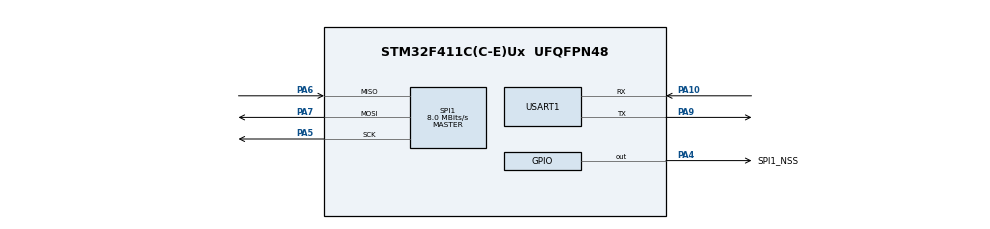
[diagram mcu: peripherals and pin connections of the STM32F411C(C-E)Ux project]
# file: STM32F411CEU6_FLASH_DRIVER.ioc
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Mcu.Family=STM32F4
Mcu.Name=STM32F411C(C-E)Ux
Mcu.Package=UFQFPN48
NVIC.PriorityGroup=NVIC_PRIORITYGROUP_4
PA10.Mode=Asynchronous
PA10.Signal=USART1_RX
PA4.GPIO_Label=SPI1_NSS
PA4.PinState=GPIO_PIN_SET
PA4.Signal=GPIO_Output
PA5.Mode=Full_Duplex_Master
PA5.Signal=SPI1_SCK
PA6.Mode=Full_Duplex_Master
PA6.Signal=SPI1_MISO
PA7.Mode=Full_Duplex_Master
PA7.Signal=SPI1_MOSI
PA9.Mode=Asynchronous
PA9.Signal=USART1_TX
ProjectManager.HeapSize=0x200
ProjectManager.StackSize=0x400
ProjectManager.TargetToolchain=CMake
RCC.AHBFreq_Value=16000000
RCC.APB1Freq_Value=16000000
RCC.APB2Freq_Value=16000000
RCC.CortexFreq_Value=16000000
RCC.HSE_VALUE=25000000
RCC.HSI_VALUE=16000000
RCC.LSE_VALUE=32768
RCC.SYSCLKFreq_VALUE=16000000
RCC.VCOOutputFreq_Value=192000000
SPI1.CalculateBaudRate=8.0 MBits/s
SPI1.Direction=SPI_DIRECTION_2LINES
SPI1.Mode=SPI_MODE_MASTER
SPI1.VirtualType=VM_MASTER
USART1.VirtualMode=VM_ASYNC
board=custom

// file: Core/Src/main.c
/* USER CODE BEGIN Header */
/**
  ******************************************************************************
  * @file           : main.c
  * @brief          : Main program body
  ******************************************************************************
  * @attention
  *
  * Copyright (c) 2026 STMicroelectronics.
  * All rights reserved.
  *
  * This software is licensed under terms that can be found in the LICENSE file
  * in the root directory of this software component.
  * If no LICENSE file comes with this software, it is provided AS-IS.
  *
  ******************************************************************************
  */
/* USER CODE END Header */
#include "main.h"

/* USER CODE BEGIN Includes */
#include "gpio.h"
#include "spi.h"
#include "usart.h"
#include "w25q128.h"
#include "uart_bootloader.h"
#include <stdio.h>
#include <string.h>
/* USER CODE END Includes */

/* USER CODE BEGIN PV */
W25Q128_Handle_t hflash;
BOOT_Handle_t hboot;
/* USER CODE END PV */

void SystemClock_Config(void);

/* USER CODE BEGIN 0 */

// Redirect printf to SWO/ITM for debug console
int _write(int file, char *ptr, int len)
{
  for (int i = 0; i < len; i++)
  {
    ITM_SendChar((*ptr++));
  }
  return len;
}

/* USER CODE END 0 */

int main(void)
{

  /* MCU Configuration--------------------------------------------------------*/

  /* Reset of all peripherals, Initializes the Flash interface and the Systick. */
  HAL_Init();

  /* Configure the system clock */
  SystemClock_Config();

  /* Initialize all configured peripherals */
  MX_GPIO_Init();
  MX_SPI1_Init();
  MX_USART1_UART_Init();
  /* USER CODE BEGIN 2 */

  // Initialize W25Q128 Flash
  W25Q128_Init(&hflash, &hspi1, SPI1_NSS_GPIO_Port, SPI1_NSS_Pin);

  // Read and verify flash ID
  uint8_t mfg_id, dev_id;
  if (W25Q128_ReadID(&hflash, &mfg_id, &dev_id) == W25Q128_OK)
  {
    // Print to both UART and Debug Console (SWO)
    printf("W25Q128 Found! MFG: 0x%02X, DEV: 0x%02X\r\n", mfg_id, dev_id);

    char msg[50];
    sprintf(msg, "W25Q128 Found! MFG: 0x%02X, DEV: 0x%02X\r\n", mfg_id, dev_id);
    HAL_UART_Transmit(&huart1, (uint8_t*)msg, strlen(msg), 1000);
  }
  else
  {
    printf("W25Q128 Error!\r\n");

    char msg[] = "W25Q128 Error!\r\n";
    HAL_UART_Transmit(&huart1, (uint8_t*)msg, strlen(msg), 1000);
  }

  // Initialize UART Bootloader
  BOOT_Init(&hboot, &huart1, &hflash);

  char ready_msg[] = "\r\nUART Bootloader Ready!\r\nWaiting for commands...\r\n";
  HAL_UART_Transmit(&huart1, (uint8_t*)ready_msg, strlen(ready_msg), 1000);

  /* USER CODE END 2 */

  /* Infinite loop */
  while (1)
  {

    /* USER CODE BEGIN 3 */
    // Process bootloader commands
    BOOT_Process(&hboot);
  }
  /* USER CODE END 3 */
}

void SystemClock_Config(void)
{
  RCC_OscInitTypeDef RCC_OscInitStruct = {0};
  RCC_ClkInitTypeDef RCC_ClkInitStruct = {0};

  /** Configure the main internal regulator output voltage
  */
  __HAL_RCC_PWR_CLK_ENABLE();
  __HAL_PWR_VOLTAGESCALING_CONFIG(PWR_REGULATOR_VOLTAGE_SCALE1);

  /** Initializes the RCC Oscillators according to the specified parameters
  * in the RCC_OscInitTypeDef structure.
  */
  RCC_OscInitStruct.OscillatorType = RCC_OSCILLATORTYPE_HSI;
  RCC_OscInitStruct.HSIState = RCC_HSI_ON;
  RCC_OscInitStruct.HSICalibrationValue = RCC_HSICALIBRATION_DEFAULT;
  RCC_OscInitStruct.PLL.PLLState = RCC_PLL_ON;
  RCC_OscInitStruct.PLL.PLLSource = RCC_PLLSOURCE_HSI;
  RCC_OscInitStruct.PLL.PLLM = 8;
  RCC_OscInitStruct.PLL.PLLN = 100;
  RCC_OscInitStruct.PLL.PLLP = RCC_PLLP_DIV2;
  RCC_OscInitStruct.PLL.PLLQ = 4;
  if (HAL_RCC_OscConfig(&RCC_OscInitStruct) != HAL_OK)
  {
    Error_Handler();
  }

  /** Initializes the CPU, AHB and APB buses clocks
  */
  RCC_ClkInitStruct.ClockType = RCC_CLOCKTYPE_HCLK|RCC_CLOCKTYPE_SYSCLK
                              |RCC_CLOCKTYPE_PCLK1|RCC_CLOCKTYPE_PCLK2;
  RCC_ClkInitStruct.SYSCLKSource = RCC_SYSCLKSOURCE_PLLCLK;
  RCC_ClkInitStruct.AHBCLKDivider = RCC_SYSCLK_DIV1;
  RCC_ClkInitStruct.APB1CLKDivider = RCC_HCLK_DIV2;
  RCC_ClkInitStruct.APB2CLKDivider = RCC_HCLK_DIV1;

  if (HAL_RCC_ClockConfig(&RCC_ClkInitStruct, FLASH_LATENCY_3) != HAL_OK)
  {
    Error_Handler();
  }
}

void Error_Handler(void)
{
  __disable_irq();
  while (1)
  {
  }
}
